VERSION 5.7 ;
  NOWIREEXTENSIONATPIN ON ;
  DIVIDERCHAR "/" ;
  BUSBITCHARS "[]" ;
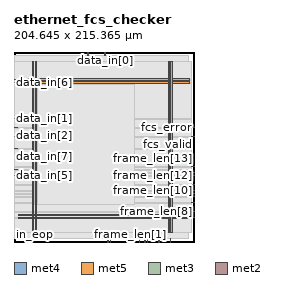
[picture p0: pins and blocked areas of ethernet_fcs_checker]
MACRO ethernet_fcs_checker
  CLASS BLOCK ;
  FOREIGN ethernet_fcs_checker ;
  ORIGIN 0.000 0.000 ;
  SIZE 204.645 BY 215.365 ;
  PIN VGND
    DIRECTION INOUT ;
    USE GROUND ;
    PORT
      LAYER met4 ;
        RECT 24.340 10.640 25.940 204.240 ;
    END
    PORT
      LAYER met4 ;
        RECT 177.940 10.640 179.540 204.240 ;
    END
    PORT
      LAYER met5 ;
        RECT 5.280 30.030 198.960 31.630 ;
    END
    PORT
      LAYER met5 ;
        RECT 5.280 183.210 198.960 184.810 ;
    END
  END VGND
  PIN VPWR
    DIRECTION INOUT ;
    USE POWER ;
    PORT
      LAYER met4 ;
        RECT 21.040 10.640 22.640 204.240 ;
    END
    PORT
      LAYER met4 ;
        RECT 174.640 10.640 176.240 204.240 ;
    END
    PORT
      LAYER met5 ;
        RECT 5.280 26.730 198.960 28.330 ;
    END
    PORT
      LAYER met5 ;
        RECT 5.280 179.910 198.960 181.510 ;
    END
  END VPWR
  PIN clk
    DIRECTION INPUT ;
    USE SIGNAL ;
    ANTENNAGATEAREA 0.852000 ;
    PORT
      LAYER met3 ;
        RECT 0.000 183.640 4.000 184.240 ;
    END
  END clk
  PIN data_in[0]
    DIRECTION INPUT ;
    USE SIGNAL ;
    ANTENNAGATEAREA 0.196500 ;
    PORT
      LAYER met2 ;
        RECT 103.130 211.365 103.410 215.365 ;
    END
  END data_in[0]
  PIN data_in[1]
    DIRECTION INPUT ;
    USE SIGNAL ;
    ANTENNAGATEAREA 0.196500 ;
    PORT
      LAYER met3 ;
        RECT 0.000 139.440 4.000 140.040 ;
    END
  END data_in[1]
  PIN data_in[2]
    DIRECTION INPUT ;
    USE SIGNAL ;
    ANTENNAGATEAREA 0.196500 ;
    PORT
      LAYER met3 ;
        RECT 0.000 129.240 4.000 129.840 ;
    END
  END data_in[2]
  PIN data_in[3]
    DIRECTION INPUT ;
    USE SIGNAL ;
    ANTENNAGATEAREA 0.196500 ;
    PORT
      LAYER met2 ;
        RECT 83.810 211.365 84.090 215.365 ;
    END
  END data_in[3]
  PIN data_in[4]
    DIRECTION INPUT ;
    USE SIGNAL ;
    ANTENNAGATEAREA 0.196500 ;
    PORT
      LAYER met3 ;
        RECT 0.000 119.040 4.000 119.640 ;
    END
  END data_in[4]
  PIN data_in[5]
    DIRECTION INPUT ;
    USE SIGNAL ;
    ANTENNAGATEAREA 0.196500 ;
    PORT
      LAYER met3 ;
        RECT 0.000 74.840 4.000 75.440 ;
    END
  END data_in[5]
  PIN data_in[6]
    DIRECTION INPUT ;
    USE SIGNAL ;
    ANTENNAGATEAREA 0.196500 ;
    PORT
      LAYER met3 ;
        RECT 0.000 180.240 4.000 180.840 ;
    END
  END data_in[6]
  PIN data_in[7]
    DIRECTION INPUT ;
    USE SIGNAL ;
    ANTENNAGATEAREA 0.196500 ;
    PORT
      LAYER met3 ;
        RECT 0.000 105.440 4.000 106.040 ;
    END
  END data_in[7]
  PIN fcs_error
    DIRECTION OUTPUT ;
    USE SIGNAL ;
    ANTENNADIFFAREA 0.445500 ;
    PORT
      LAYER met3 ;
        RECT 200.645 129.240 204.645 129.840 ;
    END
  END fcs_error
  PIN fcs_valid
    DIRECTION OUTPUT ;
    USE SIGNAL ;
    ANTENNADIFFAREA 0.445500 ;
    PORT
      LAYER met3 ;
        RECT 200.645 119.040 204.645 119.640 ;
    END
  END fcs_valid
  PIN frame_len[0]
    DIRECTION OUTPUT ;
    USE SIGNAL ;
    ANTENNADIFFAREA 0.445500 ;
    PORT
      LAYER met2 ;
        RECT 135.330 0.000 135.610 4.000 ;
    END
  END frame_len[0]
  PIN frame_len[10]
    DIRECTION OUTPUT ;
    USE SIGNAL ;
    ANTENNADIFFAREA 0.445500 ;
    PORT
      LAYER met3 ;
        RECT 200.645 57.840 204.645 58.440 ;
    END
  END frame_len[10]
  PIN frame_len[11]
    DIRECTION OUTPUT ;
    USE SIGNAL ;
    ANTENNADIFFAREA 0.445500 ;
    PORT
      LAYER met3 ;
        RECT 200.645 54.440 204.645 55.040 ;
    END
  END frame_len[11]
  PIN frame_len[12]
    DIRECTION OUTPUT ;
    USE SIGNAL ;
    ANTENNADIFFAREA 0.445500 ;
    PORT
      LAYER met3 ;
        RECT 200.645 74.840 204.645 75.440 ;
    END
  END frame_len[12]
  PIN frame_len[13]
    DIRECTION OUTPUT ;
    USE SIGNAL ;
    ANTENNADIFFAREA 0.445500 ;
    PORT
      LAYER met3 ;
        RECT 200.645 85.040 204.645 85.640 ;
    END
  END frame_len[13]
  PIN frame_len[14]
    DIRECTION OUTPUT ;
    USE SIGNAL ;
    ANTENNADIFFAREA 0.445500 ;
    PORT
      LAYER met3 ;
        RECT 200.645 78.240 204.645 78.840 ;
    END
  END frame_len[14]
  PIN frame_len[15]
    DIRECTION OUTPUT ;
    USE SIGNAL ;
    ANTENNADIFFAREA 0.445500 ;
    PORT
      LAYER met3 ;
        RECT 200.645 64.640 204.645 65.240 ;
    END
  END frame_len[15]
  PIN frame_len[1]
    DIRECTION OUTPUT ;
    USE SIGNAL ;
    ANTENNADIFFAREA 0.445500 ;
    PORT
      LAYER met2 ;
        RECT 132.110 0.000 132.390 4.000 ;
    END
  END frame_len[1]
  PIN frame_len[2]
    DIRECTION OUTPUT ;
    USE SIGNAL ;
    ANTENNADIFFAREA 0.445500 ;
    PORT
      LAYER met2 ;
        RECT 148.210 0.000 148.490 4.000 ;
    END
  END frame_len[2]
  PIN frame_len[3]
    DIRECTION OUTPUT ;
    USE SIGNAL ;
    ANTENNADIFFAREA 0.445500 ;
    PORT
      LAYER met2 ;
        RECT 141.770 0.000 142.050 4.000 ;
    END
  END frame_len[3]
  PIN frame_len[4]
    DIRECTION OUTPUT ;
    USE SIGNAL ;
    ANTENNADIFFAREA 0.445500 ;
    PORT
      LAYER met2 ;
        RECT 151.430 0.000 151.710 4.000 ;
    END
  END frame_len[4]
  PIN frame_len[5]
    DIRECTION OUTPUT ;
    USE SIGNAL ;
    ANTENNADIFFAREA 0.445500 ;
    PORT
      LAYER met3 ;
        RECT 200.645 51.040 204.645 51.640 ;
    END
  END frame_len[5]
  PIN frame_len[6]
    DIRECTION OUTPUT ;
    USE SIGNAL ;
    ANTENNADIFFAREA 0.445500 ;
    PORT
      LAYER met2 ;
        RECT 164.310 0.000 164.590 4.000 ;
    END
  END frame_len[6]
  PIN frame_len[7]
    DIRECTION OUTPUT ;
    USE SIGNAL ;
    ANTENNADIFFAREA 0.445500 ;
    PORT
      LAYER met2 ;
        RECT 177.190 0.000 177.470 4.000 ;
    END
  END frame_len[7]
  PIN frame_len[8]
    DIRECTION OUTPUT ;
    USE SIGNAL ;
    ANTENNADIFFAREA 0.445500 ;
    PORT
      LAYER met3 ;
        RECT 200.645 34.040 204.645 34.640 ;
    END
  END frame_len[8]
  PIN frame_len[9]
    DIRECTION OUTPUT ;
    USE SIGNAL ;
    ANTENNADIFFAREA 0.445500 ;
    PORT
      LAYER met3 ;
        RECT 200.645 44.240 204.645 44.840 ;
    END
  END frame_len[9]
  PIN in_eop
    DIRECTION INPUT ;
    USE SIGNAL ;
    ANTENNAGATEAREA 0.196500 ;
    PORT
      LAYER met2 ;
        RECT 12.970 0.000 13.250 4.000 ;
    END
  END in_eop
  PIN in_sop
    DIRECTION INPUT ;
    USE SIGNAL ;
    ANTENNAGATEAREA 0.196500 ;
    PORT
      LAYER met3 ;
        RECT 0.000 81.640 4.000 82.240 ;
    END
  END in_sop
  PIN in_valid
    DIRECTION INPUT ;
    USE SIGNAL ;
    ANTENNAGATEAREA 0.196500 ;
    PORT
      LAYER met2 ;
        RECT 106.350 0.000 106.630 4.000 ;
    END
  END in_valid
  PIN ready
    DIRECTION OUTPUT ;
    USE SIGNAL ;
    ANTENNADIFFAREA 0.445500 ;
    PORT
      LAYER met2 ;
        RECT 109.570 0.000 109.850 4.000 ;
    END
  END ready
  PIN rst
    DIRECTION INPUT ;
    USE SIGNAL ;
    ANTENNAGATEAREA 0.213000 ;
    PORT
      LAYER met3 ;
        RECT 200.645 27.240 204.645 27.840 ;
    END
  END rst
  OBS
      LAYER nwell ;
        RECT 5.330 10.795 198.910 204.190 ;
      LAYER li1 ;
        RECT 5.520 10.795 198.720 204.085 ;
      LAYER met1 ;
        RECT 0.530 10.640 199.020 204.240 ;
      LAYER met2 ;
        RECT 0.550 211.085 83.530 211.890 ;
        RECT 84.370 211.085 102.850 211.890 ;
        RECT 103.690 211.085 197.250 211.890 ;
        RECT 0.550 4.280 197.250 211.085 ;
        RECT 0.550 4.000 12.690 4.280 ;
        RECT 13.530 4.000 106.070 4.280 ;
        RECT 106.910 4.000 109.290 4.280 ;
        RECT 110.130 4.000 131.830 4.280 ;
        RECT 132.670 4.000 135.050 4.280 ;
        RECT 135.890 4.000 141.490 4.280 ;
        RECT 142.330 4.000 147.930 4.280 ;
        RECT 148.770 4.000 151.150 4.280 ;
        RECT 151.990 4.000 164.030 4.280 ;
        RECT 164.870 4.000 176.910 4.280 ;
        RECT 177.750 4.000 197.250 4.280 ;
      LAYER met3 ;
        RECT 0.525 184.640 200.645 204.165 ;
        RECT 4.400 183.240 200.645 184.640 ;
        RECT 0.525 181.240 200.645 183.240 ;
        RECT 4.400 179.840 200.645 181.240 ;
        RECT 0.525 140.440 200.645 179.840 ;
        RECT 4.400 139.040 200.645 140.440 ;
        RECT 0.525 130.240 200.645 139.040 ;
        RECT 4.400 128.840 200.245 130.240 ;
        RECT 0.525 120.040 200.645 128.840 ;
        RECT 4.400 118.640 200.245 120.040 ;
        RECT 0.525 106.440 200.645 118.640 ;
        RECT 4.400 105.040 200.645 106.440 ;
        RECT 0.525 86.040 200.645 105.040 ;
        RECT 0.525 84.640 200.245 86.040 ;
        RECT 0.525 82.640 200.645 84.640 ;
        RECT 4.400 81.240 200.645 82.640 ;
        RECT 0.525 79.240 200.645 81.240 ;
        RECT 0.525 77.840 200.245 79.240 ;
        RECT 0.525 75.840 200.645 77.840 ;
        RECT 4.400 74.440 200.245 75.840 ;
        RECT 0.525 65.640 200.645 74.440 ;
        RECT 0.525 64.240 200.245 65.640 ;
        RECT 0.525 58.840 200.645 64.240 ;
        RECT 0.525 57.440 200.245 58.840 ;
        RECT 0.525 55.440 200.645 57.440 ;
        RECT 0.525 54.040 200.245 55.440 ;
        RECT 0.525 52.040 200.645 54.040 ;
        RECT 0.525 50.640 200.245 52.040 ;
        RECT 0.525 45.240 200.645 50.640 ;
        RECT 0.525 43.840 200.245 45.240 ;
        RECT 0.525 35.040 200.645 43.840 ;
        RECT 0.525 33.640 200.245 35.040 ;
        RECT 0.525 28.240 200.645 33.640 ;
        RECT 0.525 26.840 200.245 28.240 ;
        RECT 0.525 10.715 200.645 26.840 ;
      LAYER met4 ;
        RECT 23.295 42.335 23.940 177.985 ;
        RECT 26.340 42.335 136.785 177.985 ;
  END
END ethernet_fcs_checker
END LIBRARY

